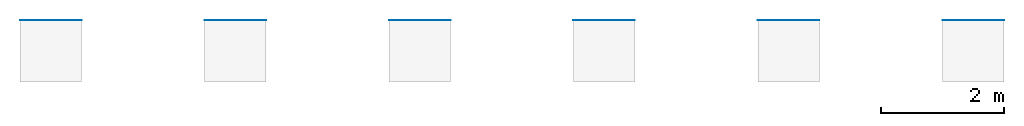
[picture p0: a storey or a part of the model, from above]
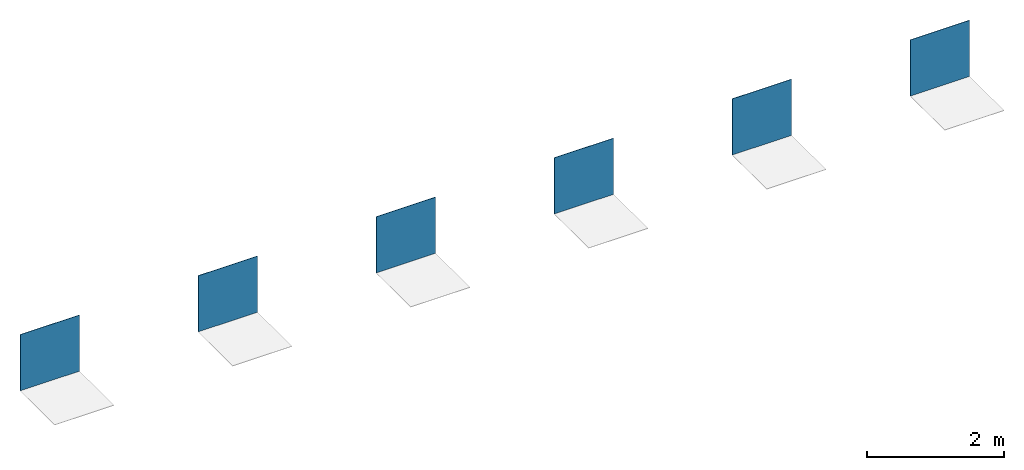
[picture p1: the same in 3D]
Properties of the parts of a building model (IFC2X3)

# File
Description: ViewDefinition [CoordinationView_V2.0]
Time: 2025-06-20T15:58:30
Written by: The EXPRESS Data Manager Version 5.02.0100.07 : 28 Aug 2013
Made in: 21.1.90.15 - Exporter 21.1.90.15 - Alternate UI 21.1.90.15
Comment: STEP Physical File produced by: The EXPRESS Data Manager Version 5.02.0100.07 : 28 Aug 2013 * Module: EDMstepFileFactory/EDMstandAlone * Creation date: Fri Jun 20 15:58:30 2025 * Host: STB002 * Database: C:\Users\LARISS~1\AppData\Local\Temp\234e31d9-e186-458c-9206-d387dea7a233\8dd01008-4684-4234-8c30-c5510eb345a5\ifc * Database version: 5507 * Database creation date: Fri Jun 20 15:58:29 2025 * Schema: IFC2X3 * Model: DataRepository.ifc * Model creation date: Fri Jun 20 15:58:30 2025 * Header model: DataRepository.ifc_HeaderModel * Header model creation date: Fri Jun 20 15:58:30 2025 * EDMuser: sdai-user * EDMgroup: sdai-group * License ID and type: 5605 : Permanent license. Expiry date: * EDMstepFileFactory options: 020000

# IfcSite, Default
RefLatitude: 42, 24, 53, 508911; RefLongitude: -71, -15, -29, -58837; RefElevation: 0 mm
Pset_ProductRequirements - Category: Project Information

# IfcBuilding
Pset_BuildingCommon - NumberOfStoreys: 1
Pset_ProductRequirements - Category: Project Information

# IfcBuildingStorey: Level:Level 1, Level 1
LongName: Level 1; Elevation: 0 mm
Pset_AirSideSystemInformation - Name: Level 1
Pset_ProductRequirements - Name: Level 1; Category: Levels

# IfcCovering: Floor:REVIGRÉS-URBAN-DECOR-29.5X29.5-RECT-STRATUS 36-ANTRACITE, Floor:REVIGRÉS-URBAN-DECOR-29.5X29.5-RECT-STRATUS 36-ANTRACITE:18907
In: Level 1
Type - PredefinedType: CLADDING; Material: REVIGRÉS-URBAN-DECOR-30X30-RECT-STRATUS 36 -ANTRACITE 7.7 mm
Type - Pset_CoveringCommon - Reference: 31211248U1; Material: Grés porcelânico
Type - Pset_ElementShading - Roughness: 304.8 mm
Type - Pset_ManufacturerTypeInformation - Manufacturer: REVIGRÉS
Type - Pset_ProductRequirements - Category: Floors
Type - Pset_QuantityTakeOff - Reference: 31211248U1
Type - IFC.REVIGRÉS-Dados do fabricante-Floor Covering - FabricanteURL: https://www.revigres.pt/; ReferenciaModelo: Urban; Acabamento: RECT; Material: Grés porcelânico; IdentificadorDoOperadorEconomico: 501840856; UrlFabricanteArtigo: https://www.revigres.pt/colecoes/urban; PaisOrigem: Portugal
Type - IFC.REVIGRÉS-Dados de desempenho-Floor Covering - Rectilinearidade: ± 0.2% máx.± 0.8 mm; Ortogonalidade: ± 0.2% máx.± 1.5 mm; PlanaridadeDaSuperficie: ± 0.3% máx. ± 1.8 mm; QualidadeDaSuperficie: Cumpre; AbsorcaoDeAgua: < 0.05%; ModuloDeRuptura: > 45 N/mm²; ResistenciaAFlexao: > 1500 N; ResistenciaAAbrasaoProfunda: < 120 mm³; DilatacaoTermicaLinear: ≤ 8,0x10-6 °C-1; ResistenciaAoChoqueTermico: Resiste; DurabilidadeResistenciaAoGeloDegelo: Resiste; ResistenciaAoEscorregamentoDIN51130: R9; ResistenciaAoEscorregamentoDIN51097: A; ResistenciaAoEscorregamentoENV51097: A; ResistenciaAoEscorregamentoENV12633: Class 1; ResistenciaAoEscorregamentoANSIA1371: ≥0,42; ResistenciaAoDeslizamentoENV12633: Class 1; ResistenciaAsManchas: Class 5; ResistenciaABaixasConcentracoesDeAcidosEAlcalis: Classe LA; ResistenciaAAltasConcentracoesDeAcidosEAlcalis: Classe HA; LibertacaoDeCadmio: 0; LibertacaoDeChumbo: 0
Type - IFC.REVIGRÉS-Dados de especificação-Floor Covering - VariacaoTonalidade: 2; NivelDeTrafego: 5; EPavimento: Sim; ERevestimento: Sim; EExterno: Sim
Type - IFC.REVIGRÉS-Dados geométricos-Floor Covering - AlturaNominal: 7.7 mm; ComprimentoNominal: 29.5 mm; LarguraNominal: 29.5 mm
Type - IFC.REVIGRÉS-Dados de sustentabilidade-Floor Covering - EnergiaTermicaExportada: 0; ItemENovo: Sim; ItemEParcialmenteReciclado: 0.29; ItemEReciclado: Sim; VidaÚtilEsperada: 50; SubstanciasPerigosas: Não; PotencialDeEsgotamentoAbioticoDosRecursosFosseis: 203; PotencialDeEsgotamentoAbioticoDosRecursosNaoFosseisMineraisEMetais: 0.000701; PotencialDeAquecimentoGlobalBiogenico: -0.48; CombustiveisFosseisComPotencialDeAquecimentoGlobal: 13.9; PotencialDeAquecimentoGlobalUsoDoSoloEMudancaDeUsoDoSolo: 0.0246; PotencialDeEutrofizacaoFraccaoDeNutrientesQueAtingemOCompartimentoFinalDeAguaDoce: 0.000189; PotencialDeEutrofizacaoFraccaoDeNutrientesQueAtingemOCompartimentoFinalMarinho: 0.0122; EnergiaRecuperada: 0.00739; ConsumoDeAguaDoce: 0.113; UtilizacaoLiquidaDeAguaDoce: 0.113; ResiduosPerigososEliminados: 0.00221; ResiduosNaoPerigososEliminados: 1.83; MassaTotalDeResiduosRadioactivosEliminados: 0.000394; EnergiaElectricaExportada: 1.55; MateriaisParaRecuperacaoDeEnergia: 0.00739; MateriaisParaReciclagem: 0.0253; UnidadeEPD: 1 m²
Type - IFC.REVIGRÉS-Dados gerais-Floor Covering - Nome: REVIGRÉS-URBAN-DECOR-29.5X29.5-RECT- ANTRACITE; TipoProduto: Prensado a seco: grupo BIa UGL | Grés porcelânico técnico; NumeroDeRegistoDAP: EPD-REV-20240006-CCC1-EN; ReferenciaDAP: -; UrlDOP: -
Classification: C3020 (Uniformat)
Pset_CoveringCommon - TotalThickness: 7.7 mm
IFC.REVIGRÉS-Dados do fabricante-Floor Covering - Type: Floor: REVIGRÉS-URBAN-DECOR-29.5X29.5-RECT-STRATUS 36-ANTRACITE
IFC.REVIGRÉS-Dados de desempenho-Floor Covering - Type: Floor: REVIGRÉS-URBAN-DECOR-29.5X29.5-RECT-STRATUS 36-ANTRACITE
IFC.REVIGRÉS-Dados de especificação-Floor Covering - Type: Floor: REVIGRÉS-URBAN-DECOR-29.5X29.5-RECT-STRATUS 36-ANTRACITE
IFC.REVIGRÉS-Dados geométricos-Floor Covering - Type: Floor: REVIGRÉS-URBAN-DECOR-29.5X29.5-RECT-STRATUS 36-ANTRACITE
IFC.REVIGRÉS-Dados de sustentabilidade-Floor Covering - Type: Floor: REVIGRÉS-URBAN-DECOR-29.5X29.5-RECT-STRATUS 36-ANTRACITE

# IfcCovering: Floor:REVIGRÉS-URBAN-DECOR-29.5X29.5-RECT-STRATUS 36-BONE, Floor:REVIGRÉS-URBAN-DECOR-29.5X29.5-RECT-STRATUS 36-BONE:21508
In: Level 1
Type - PredefinedType: CLADDING; Material: REVIGRÉS-URBAN-DECOR-30X30-RECT-STRATUS 36-BONE 7.7 mm
Type - Pset_CoveringCommon - Reference: 312112X671; Material: Grés porcelânico
Type - Pset_ElementShading - Roughness: 304.8 mm
Type - Pset_ManufacturerTypeInformation - Manufacturer: REVIGRÉS
Type - Pset_ProductRequirements - Category: Floors
Type - Pset_QuantityTakeOff - Reference: 312112X671
Type - IFC.REVIGRÉS-Dados do fabricante-Floor Covering - FabricanteURL: https://www.revigres.pt/; ReferenciaModelo: Urban; Acabamento: RECT; Material: Grés porcelânico; IdentificadorDoOperadorEconomico: 501840856; UrlFabricanteArtigo: https://www.revigres.pt/colecoes/urban; PaisOrigem: Portugal
Type - IFC.REVIGRÉS-Dados de desempenho-Floor Covering - Rectilinearidade: ± 0.2% máx.± 0.8 mm; Ortogonalidade: ± 0.2% máx.± 1.5 mm; PlanaridadeDaSuperficie: ± 0.3% máx. ± 1.8 mm; QualidadeDaSuperficie: Cumpre; AbsorcaoDeAgua: < 0.05%; ModuloDeRuptura: > 45 N/mm²; ResistenciaAFlexao: > 1500 N; ResistenciaAAbrasaoProfunda: < 120 mm³; DilatacaoTermicaLinear: ≤ 8,0x10-6 °C-1; ResistenciaAoChoqueTermico: Resiste; DurabilidadeResistenciaAoGeloDegelo: Resiste; ResistenciaAoEscorregamentoDIN51130: R9; ResistenciaAoEscorregamentoDIN51097: A; ResistenciaAoEscorregamentoENV51097: A; ResistenciaAoEscorregamentoENV12633: Class 1; ResistenciaAoEscorregamentoANSIA1371: ≥0,42; ResistenciaAoDeslizamentoENV12633: Class 1; ResistenciaAsManchas: Class 5; ResistenciaABaixasConcentracoesDeAcidosEAlcalis: Classe LA; ResistenciaAAltasConcentracoesDeAcidosEAlcalis: Classe HA; LibertacaoDeCadmio: 0; LibertacaoDeChumbo: 0
Type - IFC.REVIGRÉS-Dados de especificação-Floor Covering - VariacaoTonalidade: 2; NivelDeTrafego: 5; EPavimento: Sim; ERevestimento: Sim; EExterno: Sim
Type - IFC.REVIGRÉS-Dados geométricos-Floor Covering - AlturaNominal: 7.7 mm; ComprimentoNominal: 29.5 mm; LarguraNominal: 29.5 mm
Type - IFC.REVIGRÉS-Dados de sustentabilidade-Floor Covering - EnergiaTermicaExportada: 0; ItemENovo: Sim; ItemEParcialmenteReciclado: 0.03; ItemEReciclado: Sim; VidaÚtilEsperada: 50; SubstanciasPerigosas: Não; PotencialDeEsgotamentoAbioticoDosRecursosFosseis: 203; PotencialDeEsgotamentoAbioticoDosRecursosNaoFosseisMineraisEMetais: 0.000701; PotencialDeAquecimentoGlobalBiogenico: -0.48; CombustiveisFosseisComPotencialDeAquecimentoGlobal: 13.9; PotencialDeAquecimentoGlobalUsoDoSoloEMudancaDeUsoDoSolo: 0.0246; PotencialDeEutrofizacaoFraccaoDeNutrientesQueAtingemOCompartimentoFinalDeAguaDoce: 0.000189; PotencialDeEutrofizacaoFraccaoDeNutrientesQueAtingemOCompartimentoFinalMarinho: 0.0122; EnergiaRecuperada: 0.00739; ConsumoDeAguaDoce: 0.113; UtilizacaoLiquidaDeAguaDoce: 0.113; ResiduosPerigososEliminados: 0.00221; ResiduosNaoPerigososEliminados: 1.83; MassaTotalDeResiduosRadioactivosEliminados: 0.000394; EnergiaElectricaExportada: 1.55; MateriaisParaRecuperacaoDeEnergia: 0.00739; MateriaisParaReciclagem: 0.0253; UnidadeEPD: 1 m²
Type - IFC.REVIGRÉS-Dados gerais-Floor Covering - Nome: REVIGRÉS-URBAN-DECOR-29.5X29.5-RECT- BONE; TipoProduto: Prensado a seco: grupo BIa UGL | Grés porcelânico técnico; NumeroDeRegistoDAP: EPD-REV-20240006-CCC1-EN; ReferenciaDAP: -; UrlDOP: -
Classification: C3020 (Uniformat)
Pset_CoveringCommon - TotalThickness: 7.7 mm
IFC.REVIGRÉS-Dados do fabricante-Floor Covering - Type: Floor: REVIGRÉS-URBAN-DECOR-29.5X29.5-RECT-STRATUS 36-BONE
IFC.REVIGRÉS-Dados de desempenho-Floor Covering - Type: Floor: REVIGRÉS-URBAN-DECOR-29.5X29.5-RECT-STRATUS 36-BONE
IFC.REVIGRÉS-Dados de especificação-Floor Covering - Type: Floor: REVIGRÉS-URBAN-DECOR-29.5X29.5-RECT-STRATUS 36-BONE
IFC.REVIGRÉS-Dados geométricos-Floor Covering - Type: Floor: REVIGRÉS-URBAN-DECOR-29.5X29.5-RECT-STRATUS 36-BONE
IFC.REVIGRÉS-Dados de sustentabilidade-Floor Covering - Type: Floor: REVIGRÉS-URBAN-DECOR-29.5X29.5-RECT-STRATUS 36-BONE

# IfcCovering: Floor:REVIGRÉS-URBAN-DECOR-29.5X29.5-RECT-STRATUS 36-CRAFT, Floor:REVIGRÉS-URBAN-DECOR-29.5X29.5-RECT-STRATUS 36-CRAFT:21530
In: Level 1
Type - PredefinedType: CLADDING; Material: REVIGRÉS-URBAN-DECOR-30X30-RECT-STRATUS 36-CRAFT 7.7 mm
Type - Pset_CoveringCommon - Reference: 31211224T1; Material: Grés porcelânico
Type - Pset_ElementShading - Roughness: 304.8 mm
Type - Pset_ManufacturerTypeInformation - Manufacturer: REVIGRÉS
Type - Pset_ProductRequirements - Category: Floors
Type - Pset_QuantityTakeOff - Reference: 31211224T1
Type - IFC.REVIGRÉS-Dados do fabricante-Floor Covering - FabricanteURL: https://www.revigres.pt/; ReferenciaModelo: Urban; Acabamento: RECT; Material: Grés porcelânico; IdentificadorDoOperadorEconomico: 501840856; UrlFabricanteArtigo: https://www.revigres.pt/colecoes/urban; PaisOrigem: Portugal
Type - IFC.REVIGRÉS-Dados de desempenho-Floor Covering - Rectilinearidade: ± 0.2% máx.± 0.8 mm; Ortogonalidade: ± 0.2% máx.± 1.5 mm; PlanaridadeDaSuperficie: ± 0.3% máx. ± 1.8 mm; QualidadeDaSuperficie: Cumpre; AbsorcaoDeAgua: < 0.05%; ModuloDeRuptura: > 45 N/mm²; ResistenciaAFlexao: > 1500 N; ResistenciaAAbrasaoProfunda: < 120 mm³; DilatacaoTermicaLinear: ≤ 8,0x10-6 °C-1; ResistenciaAoChoqueTermico: Resiste; DurabilidadeResistenciaAoGeloDegelo: Resiste; ResistenciaAoEscorregamentoDIN51130: R9; ResistenciaAoEscorregamentoDIN51097: A; ResistenciaAoEscorregamentoENV51097: A; ResistenciaAoEscorregamentoENV12633: Class 1; ResistenciaAoEscorregamentoANSIA1371: ≥0,42; ResistenciaAoDeslizamentoENV12633: Class 1; ResistenciaAsManchas: Class 5; ResistenciaABaixasConcentracoesDeAcidosEAlcalis: Classe LA; ResistenciaAAltasConcentracoesDeAcidosEAlcalis: Classe HA; LibertacaoDeCadmio: 0; LibertacaoDeChumbo: 0
Type - IFC.REVIGRÉS-Dados de especificação-Floor Covering - VariacaoTonalidade: 2; NivelDeTrafego: 5; EPavimento: Sim; ERevestimento: Sim; EExterno: Sim
Type - IFC.REVIGRÉS-Dados geométricos-Floor Covering - AlturaNominal: 7.7 mm; ComprimentoNominal: 29.5 mm; LarguraNominal: 29.5 mm
Type - IFC.REVIGRÉS-Dados de sustentabilidade-Floor Covering - EnergiaTermicaExportada: 0; ItemENovo: Sim; ItemEParcialmenteReciclado: 0.19; ItemEReciclado: Sim; VidaÚtilEsperada: 50; SubstanciasPerigosas: Não; PotencialDeEsgotamentoAbioticoDosRecursosFosseis: 203; PotencialDeEsgotamentoAbioticoDosRecursosNaoFosseisMineraisEMetais: 0.000701; PotencialDeAquecimentoGlobalBiogenico: -0.48; CombustiveisFosseisComPotencialDeAquecimentoGlobal: 13.9; PotencialDeAquecimentoGlobalUsoDoSoloEMudancaDeUsoDoSolo: 0.0246; PotencialDeEutrofizacaoFraccaoDeNutrientesQueAtingemOCompartimentoFinalDeAguaDoce: 0.000189; PotencialDeEutrofizacaoFraccaoDeNutrientesQueAtingemOCompartimentoFinalMarinho: 0.0122; EnergiaRecuperada: 0.00739; ConsumoDeAguaDoce: 0.113; UtilizacaoLiquidaDeAguaDoce: 0.113; ResiduosPerigososEliminados: 0.00221; ResiduosNaoPerigososEliminados: 1.83; MassaTotalDeResiduosRadioactivosEliminados: 0.000394; EnergiaElectricaExportada: 1.55; MateriaisParaRecuperacaoDeEnergia: 0.00739; MateriaisParaReciclagem: 0.0253; UnidadeEPD: 1 m²
Type - IFC.REVIGRÉS-Dados gerais-Floor Covering - Nome: REVIGRÉS-URBAN-DECOR-29.5X29.5-RECT- CRAFT; TipoProduto: Prensado a seco: grupo BIa UGL | Grés porcelânico técnico; NumeroDeRegistoDAP: EPD-REV-20240006-CCC1-EN; ReferenciaDAP: -; UrlDOP: -
Classification: C3020 (Uniformat)
Pset_CoveringCommon - TotalThickness: 7.7 mm
IFC.REVIGRÉS-Dados do fabricante-Floor Covering - Type: Floor: REVIGRÉS-URBAN-DECOR-29.5X29.5-RECT-STRATUS 36-CRAFT
IFC.REVIGRÉS-Dados de desempenho-Floor Covering - Type: Floor: REVIGRÉS-URBAN-DECOR-29.5X29.5-RECT-STRATUS 36-CRAFT
IFC.REVIGRÉS-Dados de especificação-Floor Covering - Type: Floor: REVIGRÉS-URBAN-DECOR-29.5X29.5-RECT-STRATUS 36-CRAFT
IFC.REVIGRÉS-Dados geométricos-Floor Covering - Type: Floor: REVIGRÉS-URBAN-DECOR-29.5X29.5-RECT-STRATUS 36-CRAFT
IFC.REVIGRÉS-Dados de sustentabilidade-Floor Covering - Type: Floor: REVIGRÉS-URBAN-DECOR-29.5X29.5-RECT-STRATUS 36-CRAFT

# IfcCovering: Floor:REVIGRÉS-URBAN-DECOR-29.5X29.5-RECT-STRATUS 36-FOG, Floor:REVIGRÉS-URBAN-DECOR-29.5X29.5-RECT-STRATUS 36-FOG:21552
In: Level 1
Type - PredefinedType: CLADDING; Material: REVIGRÉS-URBAN-DECOR-30X30-RECT-STRATUS 36-FOG 7.7 mm
Type - Pset_CoveringCommon - Reference: 31211221T1; Material: Grés porcelânico
Type - Pset_ElementShading - Roughness: 304.8 mm
Type - Pset_ManufacturerTypeInformation - Manufacturer: REVIGRÉS
Type - Pset_ProductRequirements - Category: Floors
Type - Pset_QuantityTakeOff - Reference: 31211221T1
Type - IFC.REVIGRÉS-Dados do fabricante-Floor Covering - FabricanteURL: https://www.revigres.pt/; ReferenciaModelo: Urban; Acabamento: RECT; Material: Grés porcelânico; IdentificadorDoOperadorEconomico: 501840856; UrlFabricanteArtigo: https://www.revigres.pt/colecoes/urban; PaisOrigem: Portugal
Type - IFC.REVIGRÉS-Dados de desempenho-Floor Covering - Rectilinearidade: ± 0.2% máx.± 0.8 mm; Ortogonalidade: ± 0.2% máx.± 1.5 mm; PlanaridadeDaSuperficie: ± 0.3% máx. ± 1.8 mm; QualidadeDaSuperficie: Cumpre; AbsorcaoDeAgua: < 0.05%; ModuloDeRuptura: > 45 N/mm²; ResistenciaAFlexao: > 1500 N; ResistenciaAAbrasaoProfunda: < 120 mm³; DilatacaoTermicaLinear: ≤ 8,0x10-6 °C-1; ResistenciaAoChoqueTermico: Resiste; DurabilidadeResistenciaAoGeloDegelo: Resiste; ResistenciaAoEscorregamentoDIN51130: R9; ResistenciaAoEscorregamentoDIN51097: A; ResistenciaAoEscorregamentoENV51097: A; ResistenciaAoEscorregamentoENV12633: Class 1; ResistenciaAoEscorregamentoANSIA1371: ≥0,42; ResistenciaAoDeslizamentoENV12633: Class 1; ResistenciaAsManchas: Class 5; ResistenciaABaixasConcentracoesDeAcidosEAlcalis: Classe LA; ResistenciaAAltasConcentracoesDeAcidosEAlcalis: Classe HA; LibertacaoDeCadmio: 0; LibertacaoDeChumbo: 0
Type - IFC.REVIGRÉS-Dados de especificação-Floor Covering - VariacaoTonalidade: 2; NivelDeTrafego: 5; EPavimento: Sim; ERevestimento: Sim; EExterno: Sim
Type - IFC.REVIGRÉS-Dados geométricos-Floor Covering - AlturaNominal: 7.7 mm; ComprimentoNominal: 29.5 mm; LarguraNominal: 29.5 mm
Type - IFC.REVIGRÉS-Dados de sustentabilidade-Floor Covering - EnergiaTermicaExportada: 0; ItemENovo: Sim; ItemEParcialmenteReciclado: 0.23; ItemEReciclado: Sim; VidaÚtilEsperada: 50; SubstanciasPerigosas: Não; PotencialDeEsgotamentoAbioticoDosRecursosFosseis: 203; PotencialDeEsgotamentoAbioticoDosRecursosNaoFosseisMineraisEMetais: 0.000701; PotencialDeAquecimentoGlobalBiogenico: -0.48; CombustiveisFosseisComPotencialDeAquecimentoGlobal: 13.9; PotencialDeAquecimentoGlobalUsoDoSoloEMudancaDeUsoDoSolo: 0.0246; PotencialDeEutrofizacaoFraccaoDeNutrientesQueAtingemOCompartimentoFinalDeAguaDoce: 0.000189; PotencialDeEutrofizacaoFraccaoDeNutrientesQueAtingemOCompartimentoFinalMarinho: 0.0122; EnergiaRecuperada: 0.00739; ConsumoDeAguaDoce: 0.113; UtilizacaoLiquidaDeAguaDoce: 0.113; ResiduosPerigososEliminados: 0.00221; ResiduosNaoPerigososEliminados: 1.83; MassaTotalDeResiduosRadioactivosEliminados: 0.000394; EnergiaElectricaExportada: 1.55; MateriaisParaRecuperacaoDeEnergia: 0.00739; MateriaisParaReciclagem: 0.0253; UnidadeEPD: 1 m²
Type - IFC.REVIGRÉS-Dados gerais-Floor Covering - Nome: REVIGRÉS-URBAN-DECOR-29.5X29.5-RECT- FOG; TipoProduto: Prensado a seco: grupo BIa UGL | Grés porcelânico técnico; NumeroDeRegistoDAP: EPD-REV-20240006-CCC1-EN; ReferenciaDAP: -; UrlDOP: -
Classification: C3020 (Uniformat)
Pset_CoveringCommon - TotalThickness: 7.7 mm
IFC.REVIGRÉS-Dados do fabricante-Floor Covering - Type: Floor: REVIGRÉS-URBAN-DECOR-29.5X29.5-RECT-STRATUS 36-FOG
IFC.REVIGRÉS-Dados de desempenho-Floor Covering - Type: Floor: REVIGRÉS-URBAN-DECOR-29.5X29.5-RECT-STRATUS 36-FOG
IFC.REVIGRÉS-Dados de especificação-Floor Covering - Type: Floor: REVIGRÉS-URBAN-DECOR-29.5X29.5-RECT-STRATUS 36-FOG
IFC.REVIGRÉS-Dados geométricos-Floor Covering - Type: Floor: REVIGRÉS-URBAN-DECOR-29.5X29.5-RECT-STRATUS 36-FOG
IFC.REVIGRÉS-Dados de sustentabilidade-Floor Covering - Type: Floor: REVIGRÉS-URBAN-DECOR-29.5X29.5-RECT-STRATUS 36-FOG

# IfcCovering: Floor:REVIGRÉS-URBAN-DECOR-29.5X29.5-RECT-STRATUS 36-GRIS, Floor:REVIGRÉS-URBAN-DECOR-29.5X29.5-RECT-STRATUS 36-GRIS:21574
In: Level 1
Type - PredefinedType: CLADDING; Material: REVIGRÉS-URBAN-DECOR-30X30-RECT-STRATUS 36-GRIS 7.7 mm
Type - Pset_CoveringCommon - Reference: 31211222T1; Material: Grés porcelânico
Type - Pset_ElementShading - Roughness: 304.8 mm
Type - Pset_ManufacturerTypeInformation - Manufacturer: REVIGRÉS
Type - Pset_ProductRequirements - Category: Floors
Type - Pset_QuantityTakeOff - Reference: 31211222T1
Type - IFC.REVIGRÉS-Dados do fabricante-Floor Covering - FabricanteURL: https://www.revigres.pt/; ReferenciaModelo: Urban; Acabamento: RECT; Material: Grés porcelânico; IdentificadorDoOperadorEconomico: 501840856; UrlFabricanteArtigo: https://www.revigres.pt/colecoes/urban; PaisOrigem: Portugal
Type - IFC.REVIGRÉS-Dados de desempenho-Floor Covering - Rectilinearidade: ± 0.2% máx.± 0.8 mm; Ortogonalidade: ± 0.2% máx.± 1.5 mm; PlanaridadeDaSuperficie: ± 0.3% máx. ± 1.8 mm; QualidadeDaSuperficie: Cumpre; AbsorcaoDeAgua: < 0.05%; ModuloDeRuptura: > 45 N/mm²; ResistenciaAFlexao: > 1500 N; ResistenciaAAbrasaoProfunda: < 120 mm³; DilatacaoTermicaLinear: ≤ 8,0x10-6 °C-1; ResistenciaAoChoqueTermico: Resiste; DurabilidadeResistenciaAoGeloDegelo: Resiste; ResistenciaAoEscorregamentoDIN51130: R9; ResistenciaAoEscorregamentoDIN51097: A; ResistenciaAoEscorregamentoENV51097: A; ResistenciaAoEscorregamentoENV12633: Class 1; ResistenciaAoEscorregamentoANSIA1371: ≥0,42; ResistenciaAoDeslizamentoENV12633: Class 1; ResistenciaAsManchas: Class 5; ResistenciaABaixasConcentracoesDeAcidosEAlcalis: Classe LA; ResistenciaAAltasConcentracoesDeAcidosEAlcalis: Classe HA; LibertacaoDeCadmio: 0; LibertacaoDeChumbo: 0
Type - IFC.REVIGRÉS-Dados de especificação-Floor Covering - VariacaoTonalidade: 2; NivelDeTrafego: 5; EPavimento: Sim; ERevestimento: Sim; EExterno: Sim
Type - IFC.REVIGRÉS-Dados geométricos-Floor Covering - AlturaNominal: 7.7 mm; ComprimentoNominal: 29.5 mm; LarguraNominal: 29.5 mm
Type - IFC.REVIGRÉS-Dados de sustentabilidade-Floor Covering - EnergiaTermicaExportada: 0; ItemENovo: Sim; ItemEParcialmenteReciclado: 0.23; ItemEReciclado: Sim; VidaÚtilEsperada: 50; SubstanciasPerigosas: Não; PotencialDeEsgotamentoAbioticoDosRecursosFosseis: 203; PotencialDeEsgotamentoAbioticoDosRecursosNaoFosseisMineraisEMetais: 0.000701; PotencialDeAquecimentoGlobalBiogenico: -0.48; CombustiveisFosseisComPotencialDeAquecimentoGlobal: 13.9; PotencialDeAquecimentoGlobalUsoDoSoloEMudancaDeUsoDoSolo: 0.0246; PotencialDeEutrofizacaoFraccaoDeNutrientesQueAtingemOCompartimentoFinalDeAguaDoce: 0.000189; PotencialDeEutrofizacaoFraccaoDeNutrientesQueAtingemOCompartimentoFinalMarinho: 0.0122; EnergiaRecuperada: 0.00739; ConsumoDeAguaDoce: 0.113; UtilizacaoLiquidaDeAguaDoce: 0.113; ResiduosPerigososEliminados: 0.00221; ResiduosNaoPerigososEliminados: 1.83; MassaTotalDeResiduosRadioactivosEliminados: 0.000394; EnergiaElectricaExportada: 1.55; MateriaisParaRecuperacaoDeEnergia: 0.00739; MateriaisParaReciclagem: 0.0253; UnidadeEPD: 1 m²
Type - IFC.REVIGRÉS-Dados gerais-Floor Covering - Nome: REVIGRÉS-URBAN-DECOR-29.5X29.5-RECT- GRIS; TipoProduto: Prensado a seco: grupo BIa UGL | Grés porcelânico técnico; NumeroDeRegistoDAP: EPD-REV-20240006-CCC1-EN; ReferenciaDAP: -; UrlDOP: -
Classification: C3020 (Uniformat)
Pset_CoveringCommon - TotalThickness: 7.7 mm
IFC.REVIGRÉS-Dados do fabricante-Floor Covering - Type: Floor: REVIGRÉS-URBAN-DECOR-29.5X29.5-RECT-STRATUS 36-GRIS
IFC.REVIGRÉS-Dados de desempenho-Floor Covering - Type: Floor: REVIGRÉS-URBAN-DECOR-29.5X29.5-RECT-STRATUS 36-GRIS
IFC.REVIGRÉS-Dados de especificação-Floor Covering - Type: Floor: REVIGRÉS-URBAN-DECOR-29.5X29.5-RECT-STRATUS 36-GRIS
IFC.REVIGRÉS-Dados geométricos-Floor Covering - Type: Floor: REVIGRÉS-URBAN-DECOR-29.5X29.5-RECT-STRATUS 36-GRIS
IFC.REVIGRÉS-Dados de sustentabilidade-Floor Covering - Type: Floor: REVIGRÉS-URBAN-DECOR-29.5X29.5-RECT-STRATUS 36-GRIS

# IfcCovering: Floor:REVIGRÉS-URBAN-DECOR-29.5X29.5-RECT-STRATUS 36-OFFWHITE, Floor:REVIGRÉS-URBAN-DECOR-29.5X29.5-RECT-STRATUS 36-OFFWHITE:21596
In: Level 1
Type - PredefinedType: CLADDING; Material: REVIGRÉS-URBAN-DECOR-30X30-RECT-STRATUS 36-OFFWHITE 7.7 mm
Type - Pset_CoveringCommon - Reference: 31211223T1; Material: Grés porcelânico
Type - Pset_ElementShading - Roughness: 304.8 mm
Type - Pset_ManufacturerTypeInformation - Manufacturer: REVIGRÉS
Type - Pset_ProductRequirements - Category: Floors
Type - Pset_QuantityTakeOff - Reference: 31211223T1
Type - IFC.REVIGRÉS-Dados do fabricante-Floor Covering - FabricanteURL: https://www.revigres.pt/; ReferenciaModelo: Urban; Acabamento: RECT; Material: Grés porcelânico; IdentificadorDoOperadorEconomico: 501840856; UrlFabricanteArtigo: https://www.revigres.pt/colecoes/urban; PaisOrigem: Portugal
Type - IFC.REVIGRÉS-Dados de desempenho-Floor Covering - Rectilinearidade: ± 0.2% máx.± 0.8 mm; Ortogonalidade: ± 0.2% máx.± 1.5 mm; PlanaridadeDaSuperficie: ± 0.3% máx. ± 1.8 mm; QualidadeDaSuperficie: Cumpre; AbsorcaoDeAgua: < 0.05%; ModuloDeRuptura: > 45 N/mm²; ResistenciaAFlexao: > 1500 N; ResistenciaAAbrasaoProfunda: < 120 mm³; DilatacaoTermicaLinear: ≤ 8,0x10-6 °C-1; ResistenciaAoChoqueTermico: Resiste; DurabilidadeResistenciaAoGeloDegelo: Resiste; ResistenciaAoEscorregamentoDIN51130: R9; ResistenciaAoEscorregamentoDIN51097: A; ResistenciaAoEscorregamentoENV51097: A; ResistenciaAoEscorregamentoENV12633: Class 1; ResistenciaAoEscorregamentoANSIA1371: ≥0,42; ResistenciaAoDeslizamentoENV12633: Class 1; ResistenciaAsManchas: Class 5; ResistenciaABaixasConcentracoesDeAcidosEAlcalis: Classe LA; ResistenciaAAltasConcentracoesDeAcidosEAlcalis: Classe HA; LibertacaoDeCadmio: 0; LibertacaoDeChumbo: 0
Type - IFC.REVIGRÉS-Dados de especificação-Floor Covering - VariacaoTonalidade: 2; NivelDeTrafego: 5; EPavimento: Sim; ERevestimento: Sim; EExterno: Sim
Type - IFC.REVIGRÉS-Dados geométricos-Floor Covering - AlturaNominal: 7.7 mm; ComprimentoNominal: 29.5 mm; LarguraNominal: 29.5 mm
Type - IFC.REVIGRÉS-Dados de sustentabilidade-Floor Covering - EnergiaTermicaExportada: 0; ItemENovo: Sim; ItemEParcialmenteReciclado: 0.03; ItemEReciclado: Sim; VidaÚtilEsperada: 50; SubstanciasPerigosas: Não; PotencialDeEsgotamentoAbioticoDosRecursosFosseis: 203; PotencialDeEsgotamentoAbioticoDosRecursosNaoFosseisMineraisEMetais: 0.000701; PotencialDeAquecimentoGlobalBiogenico: -0.48; CombustiveisFosseisComPotencialDeAquecimentoGlobal: 13.9; PotencialDeAquecimentoGlobalUsoDoSoloEMudancaDeUsoDoSolo: 0.0246; PotencialDeEutrofizacaoFraccaoDeNutrientesQueAtingemOCompartimentoFinalDeAguaDoce: 0.000189; PotencialDeEutrofizacaoFraccaoDeNutrientesQueAtingemOCompartimentoFinalMarinho: 0.0122; EnergiaRecuperada: 0.00739; ConsumoDeAguaDoce: 0.113; UtilizacaoLiquidaDeAguaDoce: 0.113; ResiduosPerigososEliminados: 0.00221; ResiduosNaoPerigososEliminados: 1.83; MassaTotalDeResiduosRadioactivosEliminados: 0.000394; EnergiaElectricaExportada: 1.55; MateriaisParaRecuperacaoDeEnergia: 0.00739; MateriaisParaReciclagem: 0.0253; UnidadeEPD: 1 m²
Type - IFC.REVIGRÉS-Dados gerais-Floor Covering - Nome: REVIGRÉS-URBAN-DECOR-29.5X29.5-RECT- OFFWHITE; TipoProduto: Prensado a seco: grupo BIa UGL | Grés porcelânico técnico; NumeroDeRegistoDAP: EPD-REV-20240006-CCC1-EN; ReferenciaDAP: -; UrlDOP: -
Classification: C3020 (Uniformat)
Pset_CoveringCommon - TotalThickness: 7.7 mm
IFC.REVIGRÉS-Dados do fabricante-Floor Covering - Type: Floor: REVIGRÉS-URBAN-DECOR-29.5X29.5-RECT-STRATUS 36-OFFWHITE
IFC.REVIGRÉS-Dados de desempenho-Floor Covering - Type: Floor: REVIGRÉS-URBAN-DECOR-29.5X29.5-RECT-STRATUS 36-OFFWHITE
IFC.REVIGRÉS-Dados de especificação-Floor Covering - Type: Floor: REVIGRÉS-URBAN-DECOR-29.5X29.5-RECT-STRATUS 36-OFFWHITE
IFC.REVIGRÉS-Dados geométricos-Floor Covering - Type: Floor: REVIGRÉS-URBAN-DECOR-29.5X29.5-RECT-STRATUS 36-OFFWHITE
IFC.REVIGRÉS-Dados de sustentabilidade-Floor Covering - Type: Floor: REVIGRÉS-URBAN-DECOR-29.5X29.5-RECT-STRATUS 36-OFFWHITE

# IfcWallStandardCase: Basic Wall:REVIGRÉS-URBAN-DECOR-29.5X29.5-RECT-STRATUS 36-ANTRACITE, Basic Wall:REVIGRÉS-URBAN-DECOR-29.5X29.5-RECT-STRATUS 36-ANTRACITE:14093
In: Level 1
Type - PredefinedType: STANDARD; Material: REVIGRÉS-URBAN-DECOR-30X30-RECT-STRATUS 36 -ANTRACITE 7.7 mm
Type - Pset_ElementShading - Roughness: 304.8 mm
Type - Pset_ManufacturerTypeInformation - Manufacturer: REVIGRÉS
Type - Pset_ProductRequirements - Category: Walls
Type - Pset_QuantityTakeOff - Reference: 31211248U1
Type - Pset_ReinforcementBarPitchOfWall - Reference: 31211248U1
Type - Pset_WallCommon - Reference: 31211248U1; IsExternal: no
Type - IFC.REVIGRÉS-Dados do fabricante-Wall Covering - FabricanteURL: https://www.revigres.pt/; ReferenciaModelo: Urban; Acabamento: RECT; Material: Grés porcelânico; IdentificadorDoOperadorEconomico: 501840856; UrlFabricanteArtigo: https://www.revigres.pt/colecoes/urban; PaisOrigem: Portugal
Type - IFC.REVIGRÉS-Dados de desempenho-Wall Covering - Rectilinearidade: ± 0.2% máx.± 0.8 mm; Ortogonalidade: ± 0.2% máx.± 1.5 mm; PlanaridadeDaSuperficie: ± 0.3% máx. ± 1.8 mm; QualidadeDaSuperficie: Cumpre; AbsorcaoDeAgua: < 0.05%; ModuloDeRuptura: > 45 N/mm²; ResistenciaAFlexao: > 1500 N; ResistenciaAAbrasaoProfunda: < 120 mm³; DilatacaoTermicaLinear: ≤ 8,0x10-6 °C-1; ResistenciaAoChoqueTermico: Resiste; DurabilidadeResistenciaAoGeloDegelo: Resiste; ResistenciaAoEscorregamentoDIN51130: R9; ResistenciaAoEscorregamentoDIN51097: A; ResistenciaAoEscorregamentoENV51097: A; ResistenciaAoEscorregamentoENV12633: Class 1; ResistenciaAoEscorregamentoANSIA1371: ≥0,42; ResistenciaAoDeslizamentoENV12633: Class 1; ResistenciaAsManchas: Class 5; ResistenciaABaixasConcentracoesDeAcidosEAlcalis: Classe LA; ResistenciaAAltasConcentracoesDeAcidosEAlcalis: Classe HA; LibertacaoDeCadmio: 0; LibertacaoDeChumbo: 0
Type - IFC.REVIGRÉS-Dados de especificação-Wall Covering - VariacaoTonalidade: 2; NivelDeTrafego: 5; EPavimento: Sim; ERevestimento: Sim; EExterno: Sim
Type - IFC.REVIGRÉS-Dados geométricos-Wall Covering - AlturaNominal: 7.7 mm; ComprimentoNominal: 29.5 mm; LarguraNominal: 29.5 mm
Type - IFC.REVIGRÉS-Dados de sustentabilidade-Wall Covering - ItemENovo: Sim; ItemEParcialmenteReciclado: 0.29; ItemEReciclado: Sim; VidaÚtilEsperada: 50; SubstanciasPerigosas: Não; PotencialDeEsgotamentoAbioticoDosRecursosFosseis: 203; PotencialDeEsgotamentoAbioticoDosRecursosNaoFosseisMineraisEMetais: 0.000701; PotencialDeAquecimentoGlobalBiogenico: -0.48; CombustiveisFosseisComPotencialDeAquecimentoGlobal: 13.9; PotencialDeAquecimentoGlobalUsoDoSoloEMudancaDeUsoDoSolo: 0.0246; PotencialDeEutrofizacaoFraccaoDeNutrientesQueAtingemOCompartimentoFinalDeAguaDoce: 0.000189; PotencialDeEutrofizacaoFraccaoDeNutrientesQueAtingemOCompartimentoFinalMarinho: 0.0122; PotencialPrivacaoDeAguaConsumoDeAguaPonderado: 4.5; EnergiaRecuperada: 0.00739; ConsumoDeAguaDoce: 0.113; UtilizacaoLiquidaDeAguaDoce: 0.113; ResiduosPerigososEliminados: 0.00221; ResiduosNaoPerigososEliminados: 1.83; MassaTotalDeResiduosRadioactivosEliminados: 0.000394; EnergiaElectricaExportada: 1.55; EnergiaTermicaExportada: 0; MateriaisParaRecuperacaoDeEnergia: 0.00739; MateriaisParaReciclagem: 0.0253; UnidadeEPD: 1 m²
Type - IFC.REVIGRÉS-Dados gerais-Wall Covering - Nome: REVIGRÉS-URBAN-DECOR-29.5X29.5-RECT- ANTRACITE; TipoProduto: Prensado a seco: grupo BIa UGL | Grés porcelânico técnico; NumeroDeRegistoDAP: EPD-REV-20240006-CCC1-EN; ReferenciaDAP: -; UrlDOP: -
Classification: C3010 (Uniformat)
Pset_QuantityTakeOff - sets with these values: 2
Pset_WallCommon - ExtendToStructure: no; LoadBearing: no
IFC.REVIGRÉS-Dados do fabricante-Wall Covering - Type: Basic Wall: REVIGRÉS-URBAN-DECOR-29.5X29.5-RECT-STRATUS 36-ANTRACITE
IFC.REVIGRÉS-Dados de desempenho-Wall Covering - Type: Basic Wall: REVIGRÉS-URBAN-DECOR-29.5X29.5-RECT-STRATUS 36-ANTRACITE
IFC.REVIGRÉS-Dados de especificação-Wall Covering - Type: Basic Wall: REVIGRÉS-URBAN-DECOR-29.5X29.5-RECT-STRATUS 36-ANTRACITE
IFC.REVIGRÉS-Dados geométricos-Wall Covering - Type: Basic Wall: REVIGRÉS-URBAN-DECOR-29.5X29.5-RECT-STRATUS 36-ANTRACITE
IFC.REVIGRÉS-Dados de sustentabilidade-Wall Covering - Type: Basic Wall: REVIGRÉS-URBAN-DECOR-29.5X29.5-RECT-STRATUS 36-ANTRACITE

# IfcWallStandardCase: Basic Wall:REVIGRÉS-URBAN-DECOR-29.5X29.5-RECT-STRATUS 36-BONE, Basic Wall:REVIGRÉS-URBAN-DECOR-29.5X29.5-RECT-STRATUS 36-BONE:21505
In: Level 1
Type - PredefinedType: STANDARD; Material: REVIGRÉS-URBAN-DECOR-30X30-RECT-STRATUS 36-BONE 7.7 mm
Type - Pset_ElementShading - Roughness: 304.8 mm
Type - Pset_ManufacturerTypeInformation - Manufacturer: REVIGRÉS
Type - Pset_ProductRequirements - Category: Walls
Type - Pset_QuantityTakeOff - Reference: 312112X671
Type - Pset_ReinforcementBarPitchOfWall - Reference: 312112X671
Type - Pset_WallCommon - IsExternal: no; Reference: 312112X671
Type - IFC.REVIGRÉS-Dados do fabricante-Wall Covering - FabricanteURL: https://www.revigres.pt/; ReferenciaModelo: Urban; Acabamento: RECT; Material: Grés porcelânico; IdentificadorDoOperadorEconomico: 501840856; UrlFabricanteArtigo: https://www.revigres.pt/colecoes/urban; PaisOrigem: Portugal
Type - IFC.REVIGRÉS-Dados de desempenho-Wall Covering - Rectilinearidade: ± 0.2% máx.± 0.8 mm; Ortogonalidade: ± 0.2% máx.± 1.5 mm; PlanaridadeDaSuperficie: ± 0.3% máx. ± 1.8 mm; QualidadeDaSuperficie: Cumpre; AbsorcaoDeAgua: < 0.05%; ModuloDeRuptura: > 45 N/mm²; ResistenciaAFlexao: > 1500 N; ResistenciaAAbrasaoProfunda: < 120 mm³; DilatacaoTermicaLinear: ≤ 8,0x10-6 °C-1; ResistenciaAoChoqueTermico: Resiste; DurabilidadeResistenciaAoGeloDegelo: Resiste; ResistenciaAoEscorregamentoDIN51130: R9; ResistenciaAoEscorregamentoDIN51097: A; ResistenciaAoEscorregamentoENV51097: A; ResistenciaAoEscorregamentoENV12633: Class 1; ResistenciaAoEscorregamentoANSIA1371: ≥0,42; ResistenciaAoDeslizamentoENV12633: Class 1; ResistenciaAsManchas: Class 5; ResistenciaABaixasConcentracoesDeAcidosEAlcalis: Classe LA; ResistenciaAAltasConcentracoesDeAcidosEAlcalis: Classe HA; LibertacaoDeCadmio: 0; LibertacaoDeChumbo: 0
Type - IFC.REVIGRÉS-Dados de especificação-Wall Covering - VariacaoTonalidade: 2; NivelDeTrafego: 5; EPavimento: Sim; ERevestimento: Sim; EExterno: Sim
Type - IFC.REVIGRÉS-Dados geométricos-Wall Covering - AlturaNominal: 7.7 mm; ComprimentoNominal: 29.5 mm; LarguraNominal: 29.5 mm
Type - IFC.REVIGRÉS-Dados de sustentabilidade-Wall Covering - PotencialPrivacaoDeAguaConsumoDeAguaPonderado: 4.5; EnergiaTermicaExportada: 0; ItemENovo: Sim; ItemEParcialmenteReciclado: 0.03; ItemEReciclado: Sim; VidaÚtilEsperada: 50; SubstanciasPerigosas: Não; PotencialDeEsgotamentoAbioticoDosRecursosFosseis: 203; PotencialDeEsgotamentoAbioticoDosRecursosNaoFosseisMineraisEMetais: 0.000701; PotencialDeAquecimentoGlobalBiogenico: -0.48; CombustiveisFosseisComPotencialDeAquecimentoGlobal: 13.9; PotencialDeAquecimentoGlobalUsoDoSoloEMudancaDeUsoDoSolo: 0.0246; PotencialDeEutrofizacaoFraccaoDeNutrientesQueAtingemOCompartimentoFinalDeAguaDoce: 0.000189; PotencialDeEutrofizacaoFraccaoDeNutrientesQueAtingemOCompartimentoFinalMarinho: 0.0122; EnergiaRecuperada: 0.00739; ConsumoDeAguaDoce: 0.113; UtilizacaoLiquidaDeAguaDoce: 0.113; ResiduosPerigososEliminados: 0.00221; ResiduosNaoPerigososEliminados: 1.83; MassaTotalDeResiduosRadioactivosEliminados: 0.000394; EnergiaElectricaExportada: 1.55; MateriaisParaRecuperacaoDeEnergia: 0.00739; MateriaisParaReciclagem: 0.0253; UnidadeEPD: 1 m²
Type - IFC.REVIGRÉS-Dados gerais-Wall Covering - Nome: REVIGRÉS-URBAN-DECOR-29.5X29.5-RECT- BONE; TipoProduto: Prensado a seco: grupo BIa UGL | Grés porcelânico técnico; NumeroDeRegistoDAP: EPD-REV-20240006-CCC1-EN; ReferenciaDAP: -; UrlDOP: -
Classification: C3010 (Uniformat)
Pset_QuantityTakeOff - sets with these values: 2
Pset_WallCommon - ExtendToStructure: no; LoadBearing: no
IFC.REVIGRÉS-Dados do fabricante-Wall Covering - Type: Basic Wall: REVIGRÉS-URBAN-DECOR-29.5X29.5-RECT-STRATUS 36-BONE
IFC.REVIGRÉS-Dados de desempenho-Wall Covering - Type: Basic Wall: REVIGRÉS-URBAN-DECOR-29.5X29.5-RECT-STRATUS 36-BONE
IFC.REVIGRÉS-Dados de especificação-Wall Covering - Type: Basic Wall: REVIGRÉS-URBAN-DECOR-29.5X29.5-RECT-STRATUS 36-BONE
IFC.REVIGRÉS-Dados geométricos-Wall Covering - Type: Basic Wall: REVIGRÉS-URBAN-DECOR-29.5X29.5-RECT-STRATUS 36-BONE
IFC.REVIGRÉS-Dados de sustentabilidade-Wall Covering - Type: Basic Wall: REVIGRÉS-URBAN-DECOR-29.5X29.5-RECT-STRATUS 36-BONE

# IfcWallStandardCase: Basic Wall:REVIGRÉS-URBAN-DECOR-29.5X29.5-RECT-STRATUS 36-CRAFT, Basic Wall:REVIGRÉS-URBAN-DECOR-29.5X29.5-RECT-STRATUS 36-CRAFT:21527
In: Level 1
Type - PredefinedType: STANDARD; Material: REVIGRÉS-URBAN-DECOR-30X30-RECT-STRATUS 36-CRAFT 7.7 mm
Type - Pset_ElementShading - Roughness: 304.8 mm
Type - Pset_ManufacturerTypeInformation - Manufacturer: REVIGRÉS
Type - Pset_ProductRequirements - Category: Walls
Type - Pset_QuantityTakeOff - Reference: 31211224T1
Type - Pset_ReinforcementBarPitchOfWall - Reference: 31211224T1
Type - Pset_WallCommon - IsExternal: no; Reference: 31211224T1
Type - IFC.REVIGRÉS-Dados do fabricante-Wall Covering - FabricanteURL: https://www.revigres.pt/; ReferenciaModelo: Urban; Acabamento: RECT; Material: Grés porcelânico; IdentificadorDoOperadorEconomico: 501840856; UrlFabricanteArtigo: https://www.revigres.pt/colecoes/urban; PaisOrigem: Portugal
Type - IFC.REVIGRÉS-Dados de desempenho-Wall Covering - Rectilinearidade: ± 0.2% máx.± 0.8 mm; Ortogonalidade: ± 0.2% máx.± 1.5 mm; PlanaridadeDaSuperficie: ± 0.3% máx. ± 1.8 mm; QualidadeDaSuperficie: Cumpre; AbsorcaoDeAgua: < 0.05%; ModuloDeRuptura: > 45 N/mm²; ResistenciaAFlexao: > 1500 N; ResistenciaAAbrasaoProfunda: < 120 mm³; DilatacaoTermicaLinear: ≤ 8,0x10-6 °C-1; ResistenciaAoChoqueTermico: Resiste; DurabilidadeResistenciaAoGeloDegelo: Resiste; ResistenciaAoEscorregamentoDIN51130: R9; ResistenciaAoEscorregamentoDIN51097: A; ResistenciaAoEscorregamentoENV51097: A; ResistenciaAoEscorregamentoENV12633: Class 1; ResistenciaAoEscorregamentoANSIA1371: ≥0,42; ResistenciaAoDeslizamentoENV12633: Class 1; ResistenciaAsManchas: Class 5; ResistenciaABaixasConcentracoesDeAcidosEAlcalis: Classe LA; ResistenciaAAltasConcentracoesDeAcidosEAlcalis: Classe HA; LibertacaoDeCadmio: 0; LibertacaoDeChumbo: 0
Type - IFC.REVIGRÉS-Dados de especificação-Wall Covering - VariacaoTonalidade: 2; NivelDeTrafego: 5; EPavimento: Sim; ERevestimento: Sim; EExterno: Sim
Type - IFC.REVIGRÉS-Dados geométricos-Wall Covering - AlturaNominal: 7.7 mm; ComprimentoNominal: 29.5 mm; LarguraNominal: 29.5 mm
Type - IFC.REVIGRÉS-Dados de sustentabilidade-Wall Covering - PotencialPrivacaoDeAguaConsumoDeAguaPonderado: 4.5; EnergiaTermicaExportada: 0; ItemENovo: Sim; ItemEParcialmenteReciclado: 0.19; ItemEReciclado: Sim; VidaÚtilEsperada: 50; SubstanciasPerigosas: Não; PotencialDeEsgotamentoAbioticoDosRecursosFosseis: 203; PotencialDeEsgotamentoAbioticoDosRecursosNaoFosseisMineraisEMetais: 0.000701; PotencialDeAquecimentoGlobalBiogenico: -0.48; CombustiveisFosseisComPotencialDeAquecimentoGlobal: 13.9; PotencialDeAquecimentoGlobalUsoDoSoloEMudancaDeUsoDoSolo: 0.0246; PotencialDeEutrofizacaoFraccaoDeNutrientesQueAtingemOCompartimentoFinalDeAguaDoce: 0.000189; PotencialDeEutrofizacaoFraccaoDeNutrientesQueAtingemOCompartimentoFinalMarinho: 0.0122; EnergiaRecuperada: 0.00739; ConsumoDeAguaDoce: 0.113; UtilizacaoLiquidaDeAguaDoce: 0.113; ResiduosPerigososEliminados: 0.00221; ResiduosNaoPerigososEliminados: 1.83; MassaTotalDeResiduosRadioactivosEliminados: 0.000394; EnergiaElectricaExportada: 1.55; MateriaisParaRecuperacaoDeEnergia: 0.00739; MateriaisParaReciclagem: 0.0253; UnidadeEPD: 1 m²
Type - IFC.REVIGRÉS-Dados gerais-Wall Covering - Nome: REVIGRÉS-URBAN-DECOR-29.5X29.5-RECT- CRAFT; TipoProduto: Prensado a seco: grupo BIa UGL | Grés porcelânico técnico; NumeroDeRegistoDAP: EPD-REV-20240006-CCC1-EN; ReferenciaDAP: -; UrlDOP: -
Classification: C3010 (Uniformat)
Pset_QuantityTakeOff - sets with these values: 2
Pset_WallCommon - ExtendToStructure: no; LoadBearing: no
IFC.REVIGRÉS-Dados do fabricante-Wall Covering - Type: Basic Wall: REVIGRÉS-URBAN-DECOR-29.5X29.5-RECT-STRATUS 36-CRAFT
IFC.REVIGRÉS-Dados de desempenho-Wall Covering - Type: Basic Wall: REVIGRÉS-URBAN-DECOR-29.5X29.5-RECT-STRATUS 36-CRAFT
IFC.REVIGRÉS-Dados de especificação-Wall Covering - Type: Basic Wall: REVIGRÉS-URBAN-DECOR-29.5X29.5-RECT-STRATUS 36-CRAFT
IFC.REVIGRÉS-Dados geométricos-Wall Covering - Type: Basic Wall: REVIGRÉS-URBAN-DECOR-29.5X29.5-RECT-STRATUS 36-CRAFT
IFC.REVIGRÉS-Dados de sustentabilidade-Wall Covering - Type: Basic Wall: REVIGRÉS-URBAN-DECOR-29.5X29.5-RECT-STRATUS 36-CRAFT

# IfcWallStandardCase: Basic Wall:REVIGRÉS-URBAN-DECOR-29.5X29.5-RECT-STRATUS 36-FOG, Basic Wall:REVIGRÉS-URBAN-DECOR-29.5X29.5-RECT-STRATUS 36-FOG:21549
In: Level 1
Type - PredefinedType: STANDARD; Material: REVIGRÉS-URBAN-DECOR-30X30-RECT-STRATUS 36-FOG 7.7 mm
Type - Pset_ElementShading - Roughness: 304.8 mm
Type - Pset_ManufacturerTypeInformation - Manufacturer: REVIGRÉS
Type - Pset_ProductRequirements - Category: Walls
Type - Pset_QuantityTakeOff - Reference: 31211221T1
Type - Pset_ReinforcementBarPitchOfWall - Reference: 31211221T1
Type - Pset_WallCommon - IsExternal: no; Reference: 31211221T1
Type - IFC.REVIGRÉS-Dados do fabricante-Wall Covering - FabricanteURL: https://www.revigres.pt/; ReferenciaModelo: Urban; Acabamento: RECT; Material: Grés porcelânico; IdentificadorDoOperadorEconomico: 501840856; UrlFabricanteArtigo: https://www.revigres.pt/colecoes/urban; PaisOrigem: Portugal
Type - IFC.REVIGRÉS-Dados de desempenho-Wall Covering - Rectilinearidade: ± 0.2% máx.± 0.8 mm; Ortogonalidade: ± 0.2% máx.± 1.5 mm; PlanaridadeDaSuperficie: ± 0.3% máx. ± 1.8 mm; QualidadeDaSuperficie: Cumpre; AbsorcaoDeAgua: < 0.05%; ModuloDeRuptura: > 45 N/mm²; ResistenciaAFlexao: > 1500 N; ResistenciaAAbrasaoProfunda: < 120 mm³; DilatacaoTermicaLinear: ≤ 8,0x10-6 °C-1; ResistenciaAoChoqueTermico: Resiste; DurabilidadeResistenciaAoGeloDegelo: Resiste; ResistenciaAoEscorregamentoDIN51130: R9; ResistenciaAoEscorregamentoDIN51097: A; ResistenciaAoEscorregamentoENV51097: A; ResistenciaAoEscorregamentoENV12633: Class 1; ResistenciaAoEscorregamentoANSIA1371: ≥0,42; ResistenciaAoDeslizamentoENV12633: Class 1; ResistenciaAsManchas: Class 5; ResistenciaABaixasConcentracoesDeAcidosEAlcalis: Classe LA; ResistenciaAAltasConcentracoesDeAcidosEAlcalis: Classe HA; LibertacaoDeCadmio: 0; LibertacaoDeChumbo: 0
Type - IFC.REVIGRÉS-Dados de especificação-Wall Covering - VariacaoTonalidade: 2; NivelDeTrafego: 5; EPavimento: Sim; ERevestimento: Sim; EExterno: Sim
Type - IFC.REVIGRÉS-Dados geométricos-Wall Covering - AlturaNominal: 7.7 mm; ComprimentoNominal: 29.5 mm; LarguraNominal: 29.5 mm
Type - IFC.REVIGRÉS-Dados de sustentabilidade-Wall Covering - PotencialPrivacaoDeAguaConsumoDeAguaPonderado: 4.5; EnergiaTermicaExportada: 0; ItemENovo: Sim; ItemEParcialmenteReciclado: 0.23; ItemEReciclado: Sim; VidaÚtilEsperada: 50; SubstanciasPerigosas: Não; PotencialDeEsgotamentoAbioticoDosRecursosFosseis: 203; PotencialDeEsgotamentoAbioticoDosRecursosNaoFosseisMineraisEMetais: 0.000701; PotencialDeAquecimentoGlobalBiogenico: -0.48; CombustiveisFosseisComPotencialDeAquecimentoGlobal: 13.9; PotencialDeAquecimentoGlobalUsoDoSoloEMudancaDeUsoDoSolo: 0.0246; PotencialDeEutrofizacaoFraccaoDeNutrientesQueAtingemOCompartimentoFinalDeAguaDoce: 0.000189; PotencialDeEutrofizacaoFraccaoDeNutrientesQueAtingemOCompartimentoFinalMarinho: 0.0122; EnergiaRecuperada: 0.00739; ConsumoDeAguaDoce: 0.113; UtilizacaoLiquidaDeAguaDoce: 0.113; ResiduosPerigososEliminados: 0.00221; ResiduosNaoPerigososEliminados: 1.83; MassaTotalDeResiduosRadioactivosEliminados: 0.000394; EnergiaElectricaExportada: 1.55; MateriaisParaRecuperacaoDeEnergia: 0.00739; MateriaisParaReciclagem: 0.0253; UnidadeEPD: 1 m²
Type - IFC.REVIGRÉS-Dados gerais-Wall Covering - Nome: REVIGRÉS-URBAN-DECOR-29.5X29.5-RECT- FOG; TipoProduto: Prensado a seco: grupo BIa UGL | Grés porcelânico técnico; NumeroDeRegistoDAP: EPD-REV-20240006-CCC1-EN; ReferenciaDAP: -; UrlDOP: -
Classification: C3010 (Uniformat)
Pset_QuantityTakeOff - sets with these values: 2
Pset_WallCommon - ExtendToStructure: no; LoadBearing: no
IFC.REVIGRÉS-Dados do fabricante-Wall Covering - Type: Basic Wall: REVIGRÉS-URBAN-DECOR-29.5X29.5-RECT-STRATUS 36-FOG
IFC.REVIGRÉS-Dados de desempenho-Wall Covering - Type: Basic Wall: REVIGRÉS-URBAN-DECOR-29.5X29.5-RECT-STRATUS 36-FOG
IFC.REVIGRÉS-Dados de especificação-Wall Covering - Type: Basic Wall: REVIGRÉS-URBAN-DECOR-29.5X29.5-RECT-STRATUS 36-FOG
IFC.REVIGRÉS-Dados geométricos-Wall Covering - Type: Basic Wall: REVIGRÉS-URBAN-DECOR-29.5X29.5-RECT-STRATUS 36-FOG
IFC.REVIGRÉS-Dados de sustentabilidade-Wall Covering - Type: Basic Wall: REVIGRÉS-URBAN-DECOR-29.5X29.5-RECT-STRATUS 36-FOG

# IfcWallStandardCase: Basic Wall:REVIGRÉS-URBAN-DECOR-29.5X29.5-RECT-STRATUS 36-GRIS, Basic Wall:REVIGRÉS-URBAN-DECOR-29.5X29.5-RECT-STRATUS 36-GRIS:21571
In: Level 1
Type - PredefinedType: STANDARD; Material: REVIGRÉS-URBAN-DECOR-30X30-RECT-STRATUS 36-GRIS 7.7 mm
Type - Pset_ElementShading - Roughness: 304.8 mm
Type - Pset_ManufacturerTypeInformation - Manufacturer: REVIGRÉS
Type - Pset_ProductRequirements - Category: Walls
Type - Pset_QuantityTakeOff - Reference: 31211222T1
Type - Pset_ReinforcementBarPitchOfWall - Reference: 31211222T1
Type - Pset_WallCommon - IsExternal: no; Reference: 31211222T1
Type - IFC.REVIGRÉS-Dados do fabricante-Wall Covering - FabricanteURL: https://www.revigres.pt/; ReferenciaModelo: Urban; Acabamento: RECT; Material: Grés porcelânico; IdentificadorDoOperadorEconomico: 501840856; UrlFabricanteArtigo: https://www.revigres.pt/colecoes/urban; PaisOrigem: Portugal
Type - IFC.REVIGRÉS-Dados de desempenho-Wall Covering - Rectilinearidade: ± 0.2% máx.± 0.8 mm; Ortogonalidade: ± 0.2% máx.± 1.5 mm; PlanaridadeDaSuperficie: ± 0.3% máx. ± 1.8 mm; QualidadeDaSuperficie: Cumpre; AbsorcaoDeAgua: < 0.05%; ModuloDeRuptura: > 45 N/mm²; ResistenciaAFlexao: > 1500 N; ResistenciaAAbrasaoProfunda: < 120 mm³; DilatacaoTermicaLinear: ≤ 8,0x10-6 °C-1; ResistenciaAoChoqueTermico: Resiste; DurabilidadeResistenciaAoGeloDegelo: Resiste; ResistenciaAoEscorregamentoDIN51130: R9; ResistenciaAoEscorregamentoDIN51097: A; ResistenciaAoEscorregamentoENV51097: A; ResistenciaAoEscorregamentoENV12633: Class 1; ResistenciaAoEscorregamentoANSIA1371: ≥0,42; ResistenciaAoDeslizamentoENV12633: Class 1; ResistenciaAsManchas: Class 5; ResistenciaABaixasConcentracoesDeAcidosEAlcalis: Classe LA; ResistenciaAAltasConcentracoesDeAcidosEAlcalis: Classe HA; LibertacaoDeCadmio: 0; LibertacaoDeChumbo: 0
Type - IFC.REVIGRÉS-Dados de especificação-Wall Covering - VariacaoTonalidade: 2; NivelDeTrafego: 5; EPavimento: Sim; ERevestimento: Sim; EExterno: Sim
Type - IFC.REVIGRÉS-Dados geométricos-Wall Covering - AlturaNominal: 7.7 mm; ComprimentoNominal: 29.5 mm; LarguraNominal: 29.5 mm
Type - IFC.REVIGRÉS-Dados de sustentabilidade-Wall Covering - PotencialPrivacaoDeAguaConsumoDeAguaPonderado: 4.5; EnergiaTermicaExportada: 0; ItemENovo: Sim; ItemEParcialmenteReciclado: 0.23; ItemEReciclado: Sim; VidaÚtilEsperada: 50; SubstanciasPerigosas: Não; PotencialDeEsgotamentoAbioticoDosRecursosFosseis: 203; PotencialDeEsgotamentoAbioticoDosRecursosNaoFosseisMineraisEMetais: 0.000701; PotencialDeAquecimentoGlobalBiogenico: -0.48; CombustiveisFosseisComPotencialDeAquecimentoGlobal: 13.9; PotencialDeAquecimentoGlobalUsoDoSoloEMudancaDeUsoDoSolo: 0.0246; PotencialDeEutrofizacaoFraccaoDeNutrientesQueAtingemOCompartimentoFinalDeAguaDoce: 0.000189; PotencialDeEutrofizacaoFraccaoDeNutrientesQueAtingemOCompartimentoFinalMarinho: 0.0122; EnergiaRecuperada: 0.00739; ConsumoDeAguaDoce: 0.113; UtilizacaoLiquidaDeAguaDoce: 0.113; ResiduosPerigososEliminados: 0.00221; ResiduosNaoPerigososEliminados: 1.83; MassaTotalDeResiduosRadioactivosEliminados: 0.000394; EnergiaElectricaExportada: 1.55; MateriaisParaRecuperacaoDeEnergia: 0.00739; MateriaisParaReciclagem: 0.0253; UnidadeEPD: 1 m²
Type - IFC.REVIGRÉS-Dados gerais-Wall Covering - Nome: REVIGRÉS-URBAN-DECOR-29.5X29.5-RECT- GRIS; TipoProduto: Prensado a seco: grupo BIa UGL | Grés porcelânico técnico; NumeroDeRegistoDAP: EPD-REV-20240006-CCC1-EN; ReferenciaDAP: -; UrlDOP: -
Classification: C3010 (Uniformat)
Pset_QuantityTakeOff - sets with these values: 2
Pset_WallCommon - ExtendToStructure: no; LoadBearing: no
IFC.REVIGRÉS-Dados do fabricante-Wall Covering - Type: Basic Wall: REVIGRÉS-URBAN-DECOR-29.5X29.5-RECT-STRATUS 36-GRIS
IFC.REVIGRÉS-Dados de desempenho-Wall Covering - Type: Basic Wall: REVIGRÉS-URBAN-DECOR-29.5X29.5-RECT-STRATUS 36-GRIS
IFC.REVIGRÉS-Dados de especificação-Wall Covering - Type: Basic Wall: REVIGRÉS-URBAN-DECOR-29.5X29.5-RECT-STRATUS 36-GRIS
IFC.REVIGRÉS-Dados geométricos-Wall Covering - Type: Basic Wall: REVIGRÉS-URBAN-DECOR-29.5X29.5-RECT-STRATUS 36-GRIS
IFC.REVIGRÉS-Dados de sustentabilidade-Wall Covering - Type: Basic Wall: REVIGRÉS-URBAN-DECOR-29.5X29.5-RECT-STRATUS 36-GRIS

# IfcWallStandardCase: Basic Wall:REVIGRÉS-URBAN-DECOR-29.5X29.5-RECT-STRATUS 36-OFFWHITE, Basic Wall:REVIGRÉS-URBAN-DECOR-29.5X29.5-RECT-STRATUS 36-OFFWHITE:21593
In: Level 1
Type - PredefinedType: STANDARD; Material: REVIGRÉS-URBAN-DECOR-30X30-RECT-STRATUS 36-OFFWHITE 7.7 mm
Type - Pset_ElementShading - Roughness: 304.8 mm
Type - Pset_ManufacturerTypeInformation - Manufacturer: REVIGRÉS
Type - Pset_ProductRequirements - Category: Walls
Type - Pset_QuantityTakeOff - Reference: 31211223T1
Type - Pset_ReinforcementBarPitchOfWall - Reference: 31211223T1
Type - Pset_WallCommon - IsExternal: no; Reference: 31211223T1
Type - IFC.REVIGRÉS-Dados do fabricante-Wall Covering - FabricanteURL: https://www.revigres.pt/; ReferenciaModelo: Urban; Acabamento: RECT; Material: Grés porcelânico; IdentificadorDoOperadorEconomico: 501840856; UrlFabricanteArtigo: https://www.revigres.pt/colecoes/urban; PaisOrigem: Portugal
Type - IFC.REVIGRÉS-Dados de desempenho-Wall Covering - Rectilinearidade: ± 0.2% máx.± 0.8 mm; Ortogonalidade: ± 0.2% máx.± 1.5 mm; PlanaridadeDaSuperficie: ± 0.3% máx. ± 1.8 mm; QualidadeDaSuperficie: Cumpre; AbsorcaoDeAgua: < 0.05%; ModuloDeRuptura: > 45 N/mm²; ResistenciaAFlexao: > 1500 N; ResistenciaAAbrasaoProfunda: < 120 mm³; DilatacaoTermicaLinear: ≤ 8,0x10-6 °C-1; ResistenciaAoChoqueTermico: Resiste; DurabilidadeResistenciaAoGeloDegelo: Resiste; ResistenciaAoEscorregamentoDIN51130: R9; ResistenciaAoEscorregamentoDIN51097: A; ResistenciaAoEscorregamentoENV51097: A; ResistenciaAoEscorregamentoENV12633: Class 1; ResistenciaAoEscorregamentoANSIA1371: ≥0,42; ResistenciaAoDeslizamentoENV12633: Class 1; ResistenciaAsManchas: Class 5; ResistenciaABaixasConcentracoesDeAcidosEAlcalis: Classe LA; ResistenciaAAltasConcentracoesDeAcidosEAlcalis: Classe HA; LibertacaoDeCadmio: 0; LibertacaoDeChumbo: 0
Type - IFC.REVIGRÉS-Dados de especificação-Wall Covering - VariacaoTonalidade: 2; NivelDeTrafego: 5; EPavimento: Sim; ERevestimento: Sim; EExterno: Sim
Type - IFC.REVIGRÉS-Dados geométricos-Wall Covering - AlturaNominal: 7.7 mm; ComprimentoNominal: 29.5 mm; LarguraNominal: 29.5 mm
Type - IFC.REVIGRÉS-Dados de sustentabilidade-Wall Covering - PotencialPrivacaoDeAguaConsumoDeAguaPonderado: 4.5; EnergiaTermicaExportada: 0; ItemENovo: Sim; ItemEParcialmenteReciclado: 0.03; ItemEReciclado: Sim; VidaÚtilEsperada: 50; SubstanciasPerigosas: Não; PotencialDeEsgotamentoAbioticoDosRecursosFosseis: 203; PotencialDeEsgotamentoAbioticoDosRecursosNaoFosseisMineraisEMetais: 0.000701; PotencialDeAquecimentoGlobalBiogenico: -0.48; CombustiveisFosseisComPotencialDeAquecimentoGlobal: 13.9; PotencialDeAquecimentoGlobalUsoDoSoloEMudancaDeUsoDoSolo: 0.0246; PotencialDeEutrofizacaoFraccaoDeNutrientesQueAtingemOCompartimentoFinalDeAguaDoce: 0.000189; PotencialDeEutrofizacaoFraccaoDeNutrientesQueAtingemOCompartimentoFinalMarinho: 0.0122; EnergiaRecuperada: 0.00739; ConsumoDeAguaDoce: 0.113; UtilizacaoLiquidaDeAguaDoce: 0.113; ResiduosPerigososEliminados: 0.00221; ResiduosNaoPerigososEliminados: 1.83; MassaTotalDeResiduosRadioactivosEliminados: 0.000394; EnergiaElectricaExportada: 1.55; MateriaisParaRecuperacaoDeEnergia: 0.00739; MateriaisParaReciclagem: 0.0253; UnidadeEPD: 1 m²
Type - IFC.REVIGRÉS-Dados gerais-Wall Covering - Nome: REVIGRÉS-URBAN-DECOR-29.5X29.5-RECT- OFFWHITE; TipoProduto: Prensado a seco: grupo BIa UGL | Grés porcelânico técnico; NumeroDeRegistoDAP: EPD-REV-20240006-CCC1-EN; ReferenciaDAP: -; UrlDOP: -
Classification: C3010 (Uniformat)
Pset_QuantityTakeOff - sets with these values: 2
Pset_WallCommon - ExtendToStructure: no; LoadBearing: no
IFC.REVIGRÉS-Dados do fabricante-Wall Covering - Type: Basic Wall: REVIGRÉS-URBAN-DECOR-29.5X29.5-RECT-STRATUS 36-OFFWHITE
IFC.REVIGRÉS-Dados de desempenho-Wall Covering - Type: Basic Wall: REVIGRÉS-URBAN-DECOR-29.5X29.5-RECT-STRATUS 36-OFFWHITE
IFC.REVIGRÉS-Dados de especificação-Wall Covering - Type: Basic Wall: REVIGRÉS-URBAN-DECOR-29.5X29.5-RECT-STRATUS 36-OFFWHITE
IFC.REVIGRÉS-Dados geométricos-Wall Covering - Type: Basic Wall: REVIGRÉS-URBAN-DECOR-29.5X29.5-RECT-STRATUS 36-OFFWHITE
IFC.REVIGRÉS-Dados de sustentabilidade-Wall Covering - Type: Basic Wall: REVIGRÉS-URBAN-DECOR-29.5X29.5-RECT-STRATUS 36-OFFWHITE
